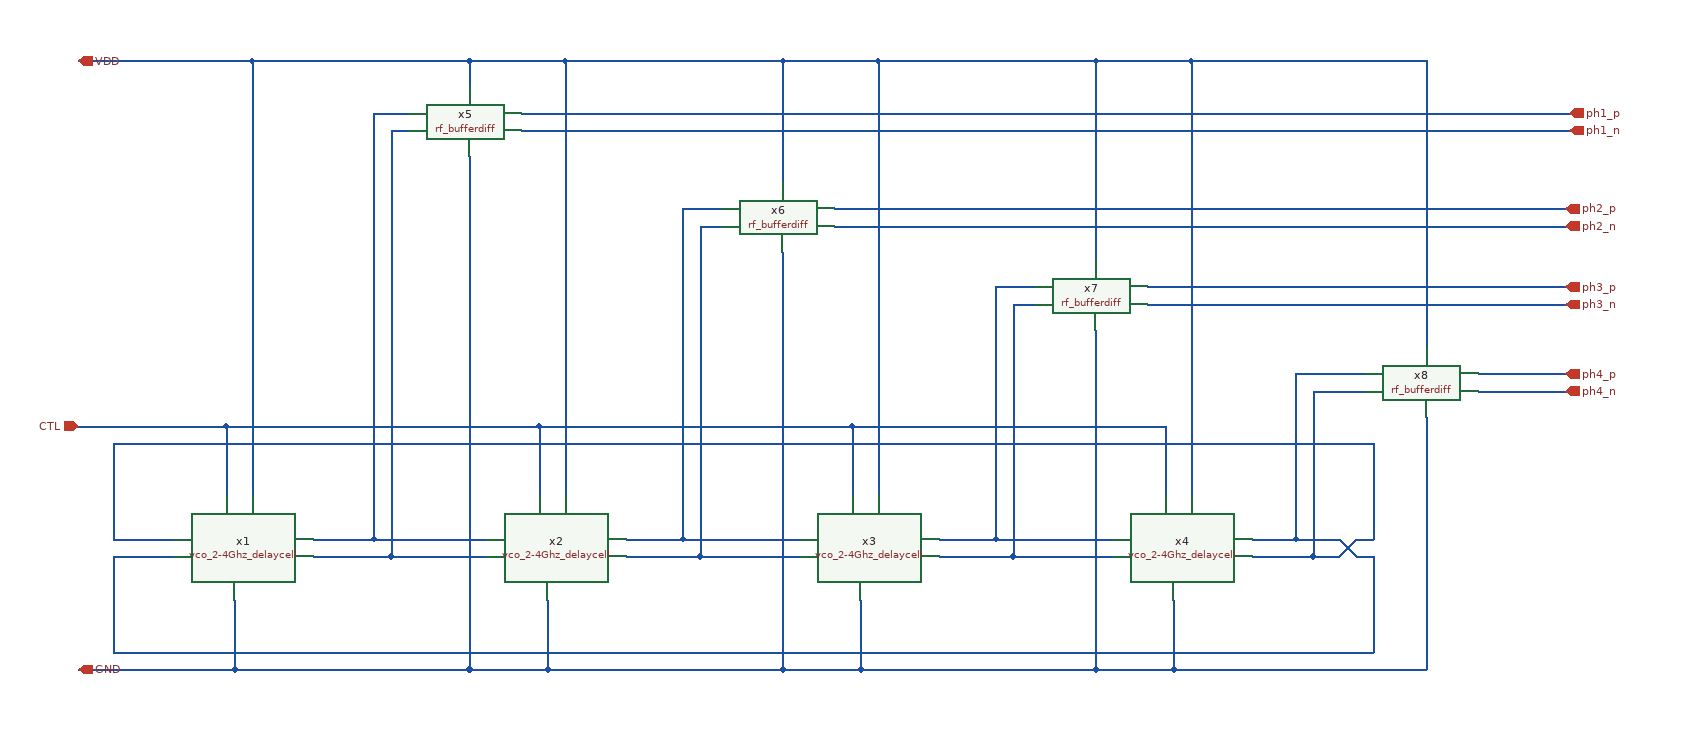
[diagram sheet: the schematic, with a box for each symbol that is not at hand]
v {xschem version=2.9.7 file_version=1.1}
G {}
V {}
S {}
E {}
N 340 -150 470 -150 {lab=#net1}
N 360 -130 470 -130 {lab=#net2}
N 695 -150 830 -150 {lab=#net3}
N 715 -130 830 -130 {lab=#net4}
N 1055 -150 1190 -150 {lab=#net5}
N 1075 -130 1190 -130 {lab=#net6}
N 1400 -150 1450 -150 {lab=#net7}
N 1450 -150 1470 -130 {lab=#net7}
N 1420 -130 1450 -130 {lab=#net8}
N 1450 -130 1470 -150 {lab=#net8}
N 1470 -130 1490 -130 {lab=#net7}
N 1490 -130 1490 -20 {lab=#net7}
N 40 -20 1490 -20 {lab=#net7}
N 40 -130 40 -20 {lab=#net7}
N 40 -130 110 -130 {lab=#net7}
N 1470 -150 1490 -150 {lab=#net8}
N 1490 -260 1490 -150 {lab=#net8}
N 40 -150 110 -150 {lab=#net8}
N 40 -260 40 -150 {lab=#net8}
N 40 -260 1490 -260 {lab=#net8}
N 170 -280 170 -200 {lab=CTL}
N 540 -80 540 0 {lab=GND}
N 900 -80 900 0 {lab=GND}
N 1260 -80 1260 0 {lab=GND}
N 450 0 540 0 {lab=GND}
N 180 -80 180 0 {lab=GND}
N 810 0 900 0 {lab=GND}
N 1170 -0 1260 0 {lab=GND}
N 170 -280 530 -280 {lab=CTL}
N 530 -280 890 -280 {lab=CTL}
N 890 -280 1250 -280 {lab=CTL}
N 450 -700 560 -700 {lab=VDD}
N 810 -700 920 -700 {lab=VDD}
N 1170 -700 1280 -700 {lab=VDD}
N 530 -280 530 -200 {lab=CTL}
N 560 -700 560 -200 {lab=VDD}
N 890 -280 890 -200 {lab=CTL}
N 920 -700 920 -200 {lab=VDD}
N 1250 -280 1250 -200 {lab=CTL}
N 1280 -700 1280 -200 {lab=VDD}
N 0 0 180 0 {lab=GND}
N 0 -280 170 -280 {lab=CTL}
N 0 -700 200 -700 {lab=VDD}
N 200 -700 200 -200 {lab=VDD}
N 1400 -340 1400 -150 {lab=#net7}
N 1075 -420 1075 -130 {lab=#net6}
N 1055 -440 1055 -150 {lab=#net5}
N 715 -510 715 -130 {lab=#net4}
N 695 -530 695 -150 {lab=#net3}
N 1280 -700 1550 -700 {lab=VDD}
N 360 -620 360 -130 {lab=#net2}
N 340 -640 340 -150 {lab=#net1}
N 1610 -340 1710 -340 {lab=ph4_p}
N 1610 -320 1710 -320 {lab=ph4_n}
N 1230 -440 1710 -440 {lab=ph3_p}
N 1230 -420 1710 -420 {lab=ph3_n}
N 870 -530 1710 -530 {lab=ph2_p}
N 870 -510 1710 -510 {lab=ph2_n}
N 510 -640 1715 -640 {lab=ph1_p}
N 510 -620 1715 -620 {lab=ph1_n}
N 1350 -150 1400 -150 {lab=#net7}
N 1350 -130 1420 -130 {lab=#net8}
N 630 -150 695 -150 {lab=#net3}
N 630 -130 715 -130 {lab=#net4}
N 270 -150 340 -150 {lab=#net1}
N 270 -130 360 -130 {lab=#net2}
N 990 -150 1055 -150 {lab=#net5}
N 990 -130 1075 -130 {lab=#net6}
N 560 -700 810 -700 {lab=VDD}
N 360 -620 380 -620 {lab=#net2}
N 340 -640 380 -640 {lab=#net1}
N 450 -590 450 0 {lab=GND}
N 450 -700 450 -670 {lab=VDD}
N 180 0 450 0 {lab=GND}
N 200 -700 450 -700 {lab=VDD}
N 695 -530 740 -530 {lab=#net3}
N 715 -510 740 -510 {lab=#net4}
N 810 -700 810 -560 {lab=VDD}
N 810 -480 810 0 {lab=GND}
N 1170 -390 1170 -0 {lab=GND}
N 1055 -440 1100 -440 {lab=#net5}
N 1075 -420 1100 -420 {lab=#net6}
N 540 0 810 0 {lab=GND}
N 900 0 1170 -0 {lab=GND}
N 1170 -700 1170 -470 {lab=VDD}
N 920 -700 1170 -700 {lab=VDD}
N 1420 -320 1480 -320 {lab=#net8}
N 1420 -320 1420 -130 {lab=#net8}
N 1400 -340 1480 -340 {lab=#net7}
N 1260 -0 1550 -0 {lab=GND}
N 1550 -290 1550 -0 {lab=GND}
N 1550 -700 1550 -370 {lab=VDD}
C {vco_2-4GHz_delaycell/vco_2-4Ghz_delaycell.sym} 180 -140 0 0 {name=x1}
C {vco_2-4GHz_delaycell/vco_2-4Ghz_delaycell.sym} 540 -140 0 0 {name=x2}
C {vco_2-4GHz_delaycell/vco_2-4Ghz_delaycell.sym} 900 -140 0 0 {name=x3}
C {vco_2-4GHz_delaycell/vco_2-4Ghz_delaycell.sym} 1260 -140 0 0 {name=x4}
C {ipin.sym} 0 -280 0 0 {name=p1 lab=CTL}
C {iopin.sym} 0 -700 0 1 {name=p6 lab=VDD}
C {iopin.sym} 0 0 0 1 {name=p7 lab=GND}
C {opin.sym} 1710 -440 0 0 {name=p2 lab=ph3_p}
C {opin.sym} 1710 -420 0 0 {name=p3 lab=ph3_n}
C {opin.sym} 1710 -340 0 0 {name=p4 lab=ph4_p}
C {opin.sym} 1710 -320 0 0 {name=p5 lab=ph4_n}
C {rf_bufferdiff/rf_bufferdiff.sym} 450 -630 0 0 {name=x5}
C {rf_bufferdiff/rf_bufferdiff.sym} 810 -520 0 0 {name=x6}
C {rf_bufferdiff/rf_bufferdiff.sym} 1170 -430 0 0 {name=x7}
C {rf_bufferdiff/rf_bufferdiff.sym} 1550 -330 0 0 {name=x8}
C {opin.sym} 1710 -530 0 0 {name=p8 lab=ph2_p}
C {opin.sym} 1710 -510 0 0 {name=p9 lab=ph2_n}
C {opin.sym} 1715 -640 0 0 {name=p10 lab=ph1_p}
C {opin.sym} 1715 -620 0 0 {name=p11 lab=ph1_n}
